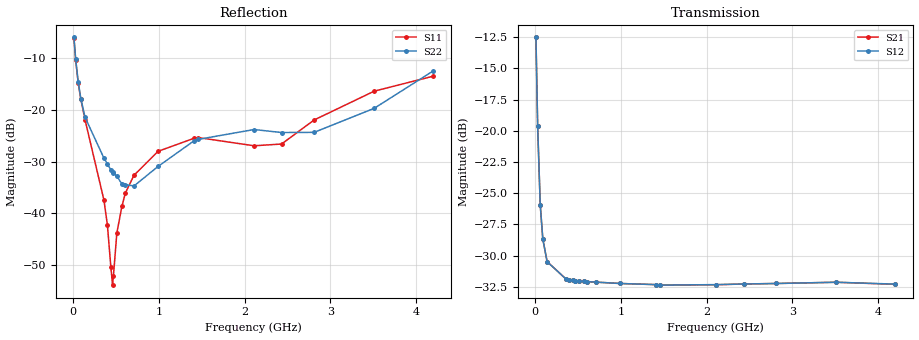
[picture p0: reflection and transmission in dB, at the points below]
! Integrated Device Technology
! Corporate Headquarters
! 6024 Silver Creek Valley Road
! San Jose, CA 95138  USA
! Phone:  1-408-284-8200
! Toll Free:  1-800-223-1366
! Webpage:  http://www.idt.com/
! Timing and RF Division
! 515 Groton Road, Suite 102
! Westford, MA 01886-6024
! Device:  F1950
! Description: 7-bit 0.25 dB Digital Step Attenuator
! Frequency:  150.0 -  4000.00 MHz
! Package:  4x4 mm Thin QFN Plastic Package: 24 pin
! Ports:  2 RF, 12 DC
!  Pin  1  = D0
!  Pin  2  = VDD
!  Pin  3  = Vmode
!  Pin  4  = GND
!  Pin  5  = RF1  =  Port 1
!  Pin  6  = GND
!  Pin  7  = GND
!  Pin  8  = GND
!  Pin  9  = GND
!  Pin 10  = GND
!  Pin 11  = GND
!  Pin 12  = GND
!  Pin 13  = GND
!  Pin 14  = RF2  =  Port 2
!  Pin 15  = GND
!  Pin 16  = LE
!  Pin 17  = CLK
!  Pin 18  = DATE
!  Pin 19  = D6
!  Pin 20  = D5
!  Pin 21  = D4
!  Pin 22  = D3
!  Pin 23  = D2
!  Pin 24  = D1
! State:  125
! Atten State:  31.25 dB
! Voltage:  +5.00 Volts
! Current:  Not Measured mA
! Data:  The device was measured on a the F195X evaluation board which has
!  individual transmission lines to the RF pins.  Data was collected
!  using a calibrated network analyzer.  The evaluation board was
!  de-embedded using a TRL calibration technique.
!  The reference plane is the edge of the package pin.
! Misc:  Board 2019
!  Action Tracker AT0250
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# GHz S dB R 50
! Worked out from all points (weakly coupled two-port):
!   420 points, 10 MHz to 4.2 GHz, reference 50 ohm
!   highest |S21| = -12.51 dB at 10 MHz (marker M1); lowest = -32.4 dB at 1.46 GHz (marker M2)
!   lowest |S11| = -53.8 dB at 460 MHz (marker M3), VSWR 1.00, Z = 49.8 - j0.0687 ohm
!   |S11| at or under -10 dB: 27.77 MHz to end of sweep
!   |S22| runs from -35.0 to -6.0 dB; largest |S21 - S12| = 6.6e-05
!   S11 on the Smith chart (normalised r, x): 10 MHz: 2.01, -1.22; 30 MHz: 1.27, -0.66; 60 MHz: 1.10, -0.37; 360 MHz: 1.01, -0.03; 4.2 GHz: 0.69, +0.17
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0.01  -6.23 -28.4  -12.51 -42.0  -12.51 -42.0  -6.02 -28.9
0.03  -10.44 -51.5  -19.65 -66.3  -19.65 -66.3  -10.25 -53.3
0.06  -14.91 -64.3  -25.91 -61.2  -25.91 -61.2  -14.63 -66.1
0.09  -17.96 -69.9  -28.66 -50.0  -28.66 -50.0  -17.85 -70.5
0.14  -21.99 -72.7  -30.47 -36.7  -30.48 -36.6  -21.47 -74.9
0.36  -37.46 -71.8  -31.87 -17.8  -31.87 -17.8  -29.34 -86.7
0.4  -42.26 -77.9  -31.92 -16.6  -31.92 -16.7  -30.45 -88.4
0.44  -50.31 -105.8  -31.97 -15.7  -31.97 -15.7  -31.58 -93.1
0.46  -53.83 -160.2  -31.99 -15.3  -31.99 -15.3  -31.97 -96.5
0.47  -52.07 170.4  -32.00 -15.1  -32.00 -15.1  -32.12 -98.1
0.51  -43.76 142.9  -32.03 -14.5  -32.02 -14.5  -32.82 -102.2
0.57  -38.54 136.2  -32.05 -13.9  -32.06 -13.9  -34.32 -113.1
0.61  -36.02 137.3  -32.08 -13.5  -32.08 -13.5  -34.45 -121.3
0.71  -32.63 138.2  -32.12 -13.0  -32.12 -13.0  -34.69 -140.9
0.99  -28.01 147.1  -32.23 -12.7  -32.23 -12.7  -30.93 179.2
1.41  -25.49 162.3  -32.32 -13.5  -32.32 -13.5  -25.98 159.9
1.46  -25.36 162.8  -32.36 -13.5  -32.36 -13.5  -25.70 158.2
2.11  -26.94 156.5  -32.33 -16.5  -32.32 -16.5  -23.80 141.5
2.43  -26.60 125.1  -32.27 -17.6  -32.27 -17.7  -24.38 130.6
2.81  -21.96 104.8  -32.23 -20.0  -32.23 -20.0  -24.35 115.1
3.51  -16.40 116.9  -32.13 -23.8  -32.13 -23.9  -19.71 112.7
4.2  -13.50 145.2  -32.30 -25.1  -32.28 -25.1  -12.47 126.9
